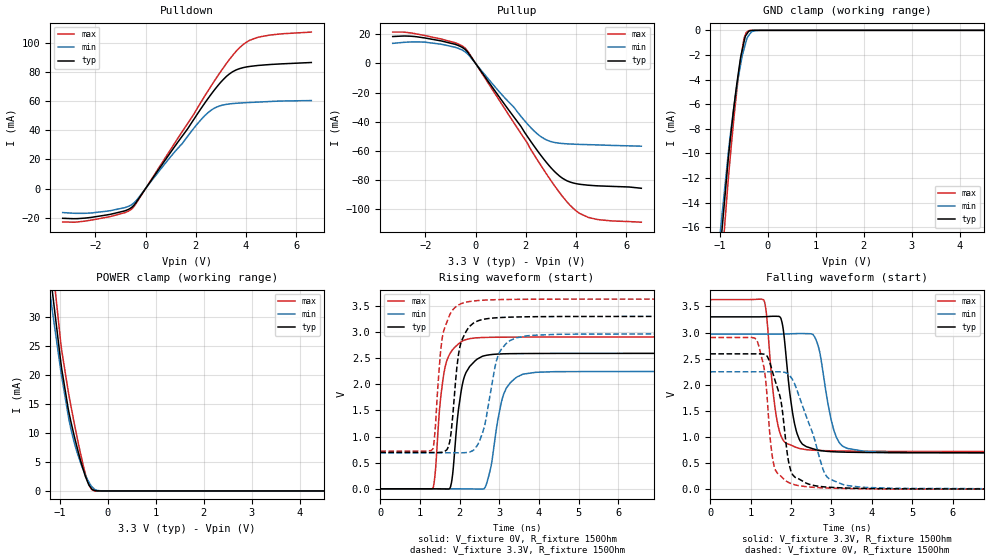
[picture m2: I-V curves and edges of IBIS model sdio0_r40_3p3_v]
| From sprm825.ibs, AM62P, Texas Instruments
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|   r40_3p3_v
[Model]   sdio0_r40_3p3_v
Model_type   I/O
Polarity   Non-Inverting
Enable   Active-High
Vinl = 0
Vinh = 0.8
Vmeas = 1.65
Vref = 3.3
Cref = 2pF
Rref = 100000
|   typ   min   max
C_comp   4.972pF   4.893pF   4.997pF
[Voltage Range]   3.3   2.97   3.63
[Temperature Range]   27   150   -40
[Pullup Reference]   3.3   2.97   3.63
[Pulldown Reference]   0   0   0
[Power Clamp Reference]   3.3   2.97   3.63
[GND Clamp Reference]   0   0   0
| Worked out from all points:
|   slope of the pulldown table from 0 to 0.495 V, typ, clamps not added: 40 ohm
|   slope of the pullup table from 0 to 0.495 V, typ, clamps not added: 40.9 ohm
|   GND clamp passes 1 mA (typ) near -0.50 V on its own axis
|   POWER clamp passes 1 mA (typ) near -0.39 V on its own axis
|   falling waveform, V_fixture 3.3V, R_fixture 150Ohm: 20-80 % time 250ps typ, 318ps min, 230ps max; typ from 3.3 V to 0.695 V
|   rising waveform, V_fixture 0V, R_fixture 150Ohm: 20-80 % time 239ps typ, 308ps min, 220ps max; typ from 0 V to 2.59 V
|   rising waveform, V_fixture 3.3V, R_fixture 150Ohm: 20-80 % time 225ps typ, 347ps min, 212ps max; typ from 0.695 V to 3.3 V
|   falling waveform, V_fixture 0V, R_fixture 150Ohm: 20-80 % time 333ps typ, 572ps min, 215ps max; typ from 2.59 V to 0 V
[Pulldown]
|   Voltage   I(typ)   I(min)   I(max)
-3.3V     -20.38mA   -16.44mA   -22.88mA
-2.706V   -20.6mA    -16.99mA   -22.89mA
-1.498V   -17.96mA   -15.4mA    -19.51mA
-825mV    -15.28mA   -13.07mA   -16.54mA
-537.9mV  -12.67mA   -10.87mA   -13.72mA
2.363V    58.69mA    50.02mA    63.57mA
2.779V    68.39mA    55.42mA    74.7mA
3.194V    76.41mA    57.61mA    85.09mA
3.452V    79.88mA    58.19mA    90.91mA
3.907V    82.92mA    58.75mA    98.97mA
4.481V    84.34mA    59.25mA    103.7mA
6.6V      86.36mA    60.28mA    107.2mA
[GND Clamp]
|   Voltage   I(typ)   I(min)   I(max)
-3.3V     -167.6mA   -127.2mA   -224.9mA
-1.013V   -18.75mA   -17.23mA   -21.53mA
-825mV    -10.45mA   -9.999mA   -12.11mA
-696.3mV  -5.878mA   -5.888mA   -6.705mA
-607.2mV  -3.274mA   -3.637mA   -3.484mA
-567.6mV  -2.2mA     -2.783mA   -2.434mA
-488.4mV  -789.6uA   -1.403mA   -561.5uA
-429mV    -244.2uA   -591.3uA   -118.2uA
-389.4mV  -55.96uA   -362.6uA   -19.71uA
-339.9mV  -12.99uA   -110.7uA   -2.821uA
-132mV    -51.25nA   -1.745uA   -80nA
6.6V      0A         0A         0A
[Pullup]
|   Voltage   I(typ)   I(min)   I(max)
-3.3V     18.39mA    13.72mA    21.44mA
-2.023V   17.42mA    14.55mA    19.09mA
-498.3mV  10.6mA     8.8mA      11.6mA
-270.6mV  6.667mA    5.678mA    7.277mA
2.402V    -58.33mA   -47.39mA   -64.49mA
2.798V    -67.3mA    -52.17mA   -75.04mA
3.194V    -74.84mA   -54.26mA   -84.94mA
3.472V    -78.72mA   -54.84mA   -91.28mA
3.887V    -81.85mA   -55.27mA   -99.21mA
4.155V    -82.75mA   -55.45mA   -102.8mA
4.788V    -83.74mA   -55.75mA   -106.6mA
6.6V      -85.46mA   -56.66mA   -108.7mA
[POWER Clamp]
|   Voltage   I(typ)   I(min)   I(max)
-3.3V     223mA      188.3mA    262.7mA
-1.201V   37.71mA    33.88mA    43.19mA
-1.191V   36.97mA    33.27mA    42.33mA
-1.152V   34.04mA    30.8mA     38.94mA
-983.4mV  22.42mA    20.88mA    25.69mA
-963.6mV  21.15mA    19.79mA    24.33mA
-805.2mV  13.3mA     12.07mA    16.24mA
-676.5mV  8.66mA     7.636mA    10.69mA
-488.4mV  3.032mA    3.154mA    3.565mA
-389.4mV  959.9uA    1.439mA    970.5uA
-290.4mV  115.1uA    394.2uA    56.37uA
6.6V      0A         0A         0A
[Ramp]
R_load = 150
|   typ   min   max
dV/dt_r   1.55495/2.38988e-10   1.3483/3.07596e-10   1.74325/2.20172e-10
dV/dt_f   1.5626/2.49912e-10   1.36811/3.16694e-10   1.74502/2.29481e-10
[Falling Waveform]
V_fixture = 3.3V
V_fixture_min = 2.97V
V_fixture_max = 3.63V
R_fixture = 150Ohm
C_fixture = 0F
|   Time   V(typ)   V(min)   V(max)
0s        3.3V       2.969V     3.63V
1.325ns   3.303V     2.97V      3.625V
1.675ns   3.31V      2.97V      1.228V
1.795ns   3.117V     2.971V     951mV
1.97ns    1.833V     2.975V     852.9mV
2.12ns    1.143V     2.979V     802.2mV
2.6ns     760.2mV    2.891V     744.2mV
3.055ns   716.1mV    1.139V     733.5mV
3.385ns   708.1mV    783.2mV    730.2mV
10ns      695.3mV    689.2mV    721.4mV
[Rising Waveform]
V_fixture = 0V
V_fixture_min = 0V
V_fixture_max = 0V
R_fixture = 150Ohm
C_fixture = 0F
|   Time   V(typ)   V(min)   V(max)
0s        312.6uV    651.3uV    206.8uV
1.325ns   271.9uV    472.7uV    9.314mV
1.63ns    -2.65mV    342.1uV    2.318V
1.795ns   124.6mV    381.9uV    2.633V
1.97ns    1.516V     258.5uV    2.772V
2.12ns    2.147V     -457.6uV   2.845V
2.645ns   2.55V      33.84mV    2.896V
3.105ns   2.582V     1.802V     2.901V
3.59ns    2.587V     2.192V     2.903V
10ns      2.592V     2.248V     2.906V
[Rising Waveform]
V_fixture = 3.3V
V_fixture_min = 2.97V
V_fixture_max = 3.63V
R_fixture = 150Ohm
C_fixture = 0F
|   Time   V(typ)   V(min)   V(max)
0s        695.3mV    689.2mV    721.4mV
1.32ns    695.3mV    689.1mV    756.6mV
1.575ns   702.1mV    689mV      2.945V
1.76ns    945.5mV    689mV      3.344V
1.93ns    2.325V     689mV      3.497V
2.045ns   2.82V      689.4mV    3.543V
2.485ns   3.219V     889.6mV    3.603V
2.975ns   3.274V     2.567V     3.619V
3.425ns   3.287V     2.887V     3.624V
10ns      3.3V       2.969V     3.63V
[Falling Waveform]
|Gnd
V_fixture = 0V
V_fixture_min = 0V
V_fixture_max = 0V
R_fixture = 150Ohm
C_fixture = 0F
|   Time   V(typ)   V(min)   V(max)
0s        2.592V     2.248V     2.906V
1.15ns    2.592V     2.248V     2.855V
1.35ns    2.58V      2.248V     2.228V
1.485ns   2.399V     2.248V     961.8mV
1.575ns   2.155V     2.248V     461.4mV
1.75ns    1.689V     2.247V     246.9mV
2.005ns   330.4mV    2.134V     105.5mV
2.83ns    43.67mV    308.5mV    23.86mV
3.28ns    24.19mV    90.69mV    13.79mV
10ns      313.4uV    651.4uV    206.8uV
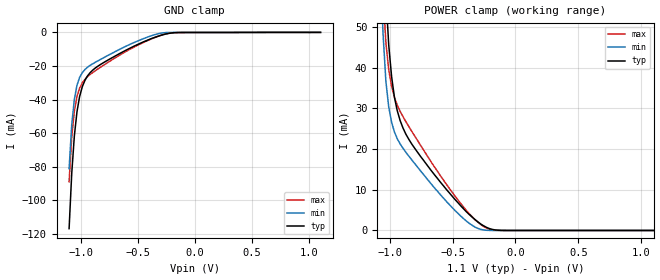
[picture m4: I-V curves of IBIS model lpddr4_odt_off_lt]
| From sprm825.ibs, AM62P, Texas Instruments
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|   Model lpddr4_odt_off_lt
[Model] lpddr4_odt_off_lt
Model_type Input
Polarity   Non-Inverting
Enable   Active-High
Vinl =  0.113V
Vinh =  0.253V
C_comp   2.918pF   2.672pF   2.927pF
[Model Spec]
Vinh   0.253V   0.247V   0.265V
Vinl   0.113V   0.107V   0.125V
[Temperature Range]   25.000   -40.000   -40.000
[Voltage Range]   1.100V   1.060V   1.170V
[C Comp Corner]
C_comp   2.927pF   2.672pF   2.918pF
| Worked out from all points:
|   GND clamp passes 1 mA (typ) near -0.26 V on its own axis
|   POWER clamp passes 1 mA (typ) near -0.24 V on its own axis
[GND_clamp]
|Voltage   I(typ)   I(min)   I(max)
-1.1V     -116.8mA   -81.16mA   -88.94mA
-1.077V   -83.94mA   -55mA      -62.39mA
-1.054V   -61.59mA   -39.8mA    -46.82mA
-1.031V   -47.19mA   -31.45mA   -38.12mA
-1.008V   -38.15mA   -26.79mA   -33.14mA
-985mV    -32.43mA   -23.99mA   -30.06mA
-962mV    -28.65mA   -22.13mA   -27.97mA
-917mV    -24.04mA   -19.67mA   -25.1mA
-871mV    -21.21mA   -17.8mA    -22.84mA
-481mV    -6.591mA   -4.569mA   -7.005mA
-229mV    -598.7uA   -44.99uA   -573.1uA
1.1V      0A         0A         0A
[POWER_clamp]
|Voltage   I(typ)   I(min)   I(max)
-1.1V     158.5mA    112mA      122.8mA
-1.054V   78.44mA    48.88mA    58.83mA
-1.031V   58.13mA    36.85mA    46.38mA
-1.008V   45.62mA    30.39mA    39.55mA
-985mV    37.81mA    26.62mA    35.43mA
-940mV    29.44mA    22.56mA    30.81mA
-894mV    25.17mA    20.21mA    27.98mA
-825mV    21.27mA    17.36mA    24.38mA
-367mV    3.909mA    1.752mA    4.095mA
-252mV    1.128mA    118.9uA    961uA
-160mV    128.1uA    2.966uA    54.3uA
1.1V      0A         0A         0A
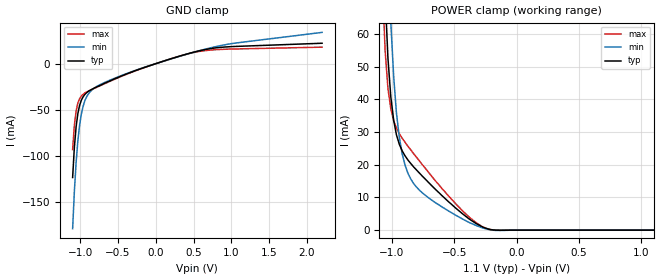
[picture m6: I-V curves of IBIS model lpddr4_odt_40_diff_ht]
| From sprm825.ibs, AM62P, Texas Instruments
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|   Model lpddr4_odt_40_diff_ht
[Model] lpddr4_odt_40_diff_ht
Model_type Input
Polarity   Non-Inverting
Enable   Active-High
Vinl =  0.113V
Vinh =  0.253V
C_comp   2.330pF   2.244pF   2.381pF
[Model Spec]
Vinh   0.253V   0.247V   0.265V
Vinl   0.113V   0.107V   0.125V
[Temperature Range]   25.000   0.125k   -40.000
[Voltage Range]   1.100V   1.060V   1.170V
[C Comp Corner]
C_comp   2.330pF   2.244pF   2.381pF
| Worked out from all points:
|   GND clamp passes 1 mA (typ) near -0.04 V on its own axis
|   POWER clamp passes 1 mA (typ) near -0.27 V on its own axis
[GND_clamp]
|Voltage   I(typ)   I(min)   I(max)
-1.1V     -123.6mA   -179.1mA   -93.24mA
-1.077V   -90.87mA   -138.8mA   -66.85mA
-1.054V   -68.63mA   -107.4mA   -51.44mA
-1.031V   -54.34mA   -83.93mA   -42.91mA
-1.008V   -45.42mA   -66.93mA   -38.11mA
-985mV    -39.79mA   -54.93mA   -35.23mA
-940mV    -33.58mA   -40.61mA   -31.98mA
-825mV    -27.02mA   -27.23mA   -27.3mA
-321mV    -9.177mA   -8.851mA   -9.456mA
550mV     13.39mA    13.42mA    12.85mA
940mV     18.16mA    20.83mA    15.65mA
2.2V      22.11mA    33.88mA    17.87mA
[POWER_clamp]
|Voltage   I(typ)   I(min)   I(max)
-1.1V     150.5mA    232.9mA    117.5mA
-1.077V   103.3mA    169.5mA    77.34mA
-1.054V   72.09mA    121.9mA    55.08mA
-1.031V   52.53mA    87.43mA    43.31mA
-1.008V   40.71mA    63.38mA    37.09mA
-963mV    29.15mA    35.85mA    31.21mA
-940mV    26.25mA    28.37mA    29.49mA
-871mV    21.44mA    17.41mA    25.65mA
-710mV    14.75mA    10.02mA    17.87mA
-390mV    3.719mA    2.548mA    4.353mA
-229mV    374uA      250uA      359.7uA
1.1V      0A         0A         0A
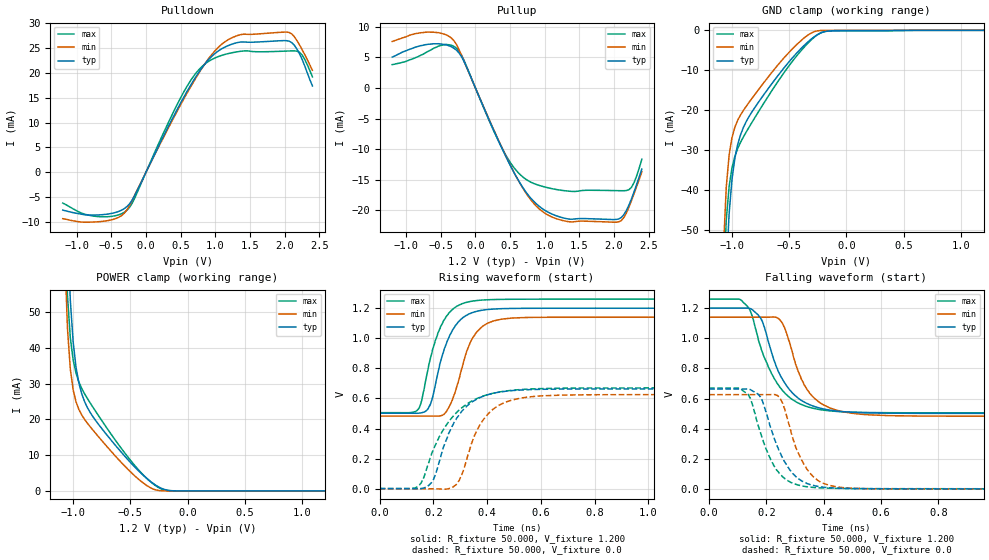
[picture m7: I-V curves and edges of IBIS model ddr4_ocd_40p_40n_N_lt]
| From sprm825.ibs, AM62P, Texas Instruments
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|   Model ddr4_ocd_40p_40n_N_lt
[Model] ddr4_ocd_40p_40n_N_lt
Model_type I/O
Polarity   Non-Inverting
Enable   Active-High
Vinl =  0.700V
Vinh =  0.900V
Vmeas =  0.600V
C_comp   2.139pF   2.037pF   2.245pF
[Model Spec]
Vinh   0.900V   0.820V   0.980V
Vinl   0.700V   0.620V   0.780V
Vmeas   0.600V   NA   NA
[Temperature Range]   25.000   -40.000   -40.000
[Voltage Range]   1.200V   1.140V   1.260V
[Pullup Reference]   1.200V   1.140V   1.260V
[Pulldown Reference]   0.0V   0.0V   0.0V
[C Comp Corner]
C_comp   2.139pF   2.037pF   2.245pF
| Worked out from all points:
|   slope of the pulldown table from 0 to 0.18 V, typ, clamps not added: 34.6 ohm
|   slope of the pullup table from 0 to 0.18 V, typ, clamps not added: 37.8 ohm
|   GND clamp passes 1 mA (typ) near -0.25 V on its own axis
|   POWER clamp passes 1 mA (typ) near -0.25 V on its own axis
|   rising waveform, R_fixture 50.000, V_fixture 1.200: 20-80 % time 72.1ps typ, 73.2ps min, 71ps max; typ from 0.502 V to 1.2 V
|   rising waveform, R_fixture 50.000, V_fixture 0.0: 20-80 % time 99.8ps typ, 93.5ps min, 129ps max; typ from 0.002 V to 0.664 V
|   falling waveform, R_fixture 50.000, V_fixture 1.200: 20-80 % time 93.8ps typ, 86.5ps min, 99.1ps max; typ from 1.2 V to 0.502 V
|   falling waveform, R_fixture 50.000, V_fixture 0.0: 20-80 % time 84.5ps typ, 76.2ps min, 78.6ps max; typ from 0.664 V to 0.002 V
[Pulldown]
|Voltage   I(typ)   I(min)   I(max)
-1.2V     -7.604mA   -9.324mA   -6.19mA
-718mV    -8.594mA   -9.972mA   -8.873mA
-421mV    -8.003mA   -9.223mA   -8.661mA
-272mV    -6.865mA   -7.502mA   -7.604mA
-161mV    -4.642mA   -4.549mA   -5.134mA
619mV     16.89mA    16.55mA    17.9mA
841mV     21.63mA    21.63mA    21.67mA
1.138V    25.17mA    26.22mA    23.69mA
1.398V    26.19mA    27.74mA    24.38mA
2.066V    26.34mA    28.1mA     24.39mA
2.252V    22.69mA    24.65mA    23.56mA
2.4V      17.35mA    20.51mA    19.18mA
[Pullup]
|Voltage   I(typ)   I(min)   I(max)
-1.2V     5.023mA    7.567mA    3.798mA
-606mV    7.199mA    9.095mA    6.434mA
-272mV    6.144mA    7.054mA    6.483mA
-161mV    4.243mA    4.267mA    4.42mA
247mV     -6.49mA    -6.402mA   -6.582mA
507mV     -12.75mA   -12.69mA   -12.24mA
804mV     -18.06mA   -18.33mA   -15.4mA
1.064V    -20.37mA   -20.85mA   -16.34mA
1.361V    -21.41mA   -21.85mA   -16.86mA
2.066V    -21.38mA   -21.86mA   -16.77mA
2.252V    -18.06mA   -18.36mA   -16.19mA
2.4V      -13.24mA   -13.7mA    -11.64mA
[GND_clamp]
|Voltage   I(typ)   I(min)   I(max)
-1.2V     -396.3mA   -359.8mA   -370.5mA
-1.075V   -83.02mA   -54.49mA   -63.08mA
-1.05V    -59.94mA   -39.12mA   -47.32mA
-1.025V   -45.76mA   -31.12mA   -38.96mA
-1V       -37.22mA   -26.8mA    -34.32mA
-950mV    -28.5mA    -22.45mA   -29.5mA
-900mV    -24.23mA   -19.99mA   -26.62mA
-800mV    -19.26mA   -16.03mA   -21.8mA
-550mV    -9.545mA   -7.027mA   -10.77mA
-350mV    -3.249mA   -1.463mA   -3.61mA
-150mV    -148.5uA   -4.426uA   -178.6uA
1.2V      0A         0A         0A
[POWER_clamp]
|Voltage   I(typ)   I(min)   I(max)
-1.2V     594.8mA    611.1mA    623.3mA
-1.075V   106.2mA    68.15mA    77.8mA
-1.05V    73.23mA    45.49mA    54.67mA
-1.025V   53.34mA    34.11mA    42.85mA
-1V       41.61mA    28.23mA    36.57mA
-975mV    34.56mA    24.88mA    32.87mA
-950mV    30.12mA    22.73mA    30.42mA
-900mV    24.94mA    19.97mA    27.12mA
-825mV    20.64mA    16.92mA    23.28mA
-375mV    4.008mA    1.916mA    4.058mA
-175mV    200.6uA    5.445uA    99.21uA
1.2V      0A         0A         0A
[Ramp]
| variable   typ   min   max
dV/dt_r   0.397/99.237p   0.376/93.412p   0.400/0.130n
dV/dt_f   0.419/93.068p   0.394/85.537p   0.452/99.140p
R_load = 60.000
[Rising Waveform]
R_fixture= 50.000
V_fixture= 1.200
V_fixture_min= 1.140
V_fixture_max= 1.260
|time   V(typ)   V(min)   V(max)
0s        502.1mV    483mV      505.9mV
145ps     502.5mV    483mV      532.4mV
187ps     553.2mV    483mV      853.3mV
238ps     912.8mV    492.9mV    1.117V
280ps     1.08V      637.4mV    1.204V
323ps     1.152V     909.8mV    1.238V
347ps     1.171V     1.005V     1.247V
424ps     1.194V     1.115V     1.257V
544ps     1.199V     1.138V     1.259V
3ns       1.2V       1.14V      1.26V
[Rising Waveform]
R_fixture= 50.000
V_fixture= 0.0
V_fixture_min= 0.0
V_fixture_max= 0.0
|time   V(typ)   V(min)   V(max)
0s        1.58mV     142.5uV    2.722mV
136ps     1.49mV     136.7uV    9.821mV
161ps     4.365mV    137.8uV    60.31mV
185ps     27.05mV    133uV      187.8mV
274ps     429.4mV    13.83mV    483.7mV
304ps     510.5mV    84.76mV    535.9mV
381ps     611.7mV    448mV      613.6mV
471ps     648.5mV    577.3mV    650mV
791ps     663.3mV    624.8mV    669.7mV
3ns       663.6mV    626.6mV    670.2mV
[Falling Waveform]
R_fixture= 50.000
V_fixture= 1.200
V_fixture_min= 1.140
V_fixture_max= 1.260
|time   V(typ)   V(min)   V(max)
0s        1.2V       1.14V      1.26V
106ps     1.2V       1.14V      1.259V
139ps     1.199V     1.14V      1.199V
184ps     1.12V      1.14V      916.6mV
245ps     767.3mV    1.126V     681.9mV
263ps     706.6mV    1.071V     639.9mV
330ps     578.9mV    697.1mV    555.1mV
399ps     531.6mV    558.6mV    523.8mV
629ps     503.6mV    487.3mV    506.8mV
3ns       502.1mV    483mV      505.9mV
[Falling Waveform]
R_fixture= 50.000
V_fixture= 0.0
V_fixture_min= 0.0
V_fixture_max= 0.0
|time   V(typ)   V(min)   V(max)
0s        663.6mV    626.5mV    670.2mV
136ps     663.4mV    626.5mV    628.5mV
184ps     594mV      626.5mV    346.6mV
241ps     270.2mV    616.1mV    115.3mV
263ps     182.7mV    535mV      72.65mV
291ps     105.1mV    345.1mV    40.51mV
349ps     33.08mV    113.9mV    14.25mV
421ps     9.467mV    24.6mV     6.341mV
559ps     3.116mV    2.909mV    3.715mV
3ns       1.579mV    143.3uV    2.722mV
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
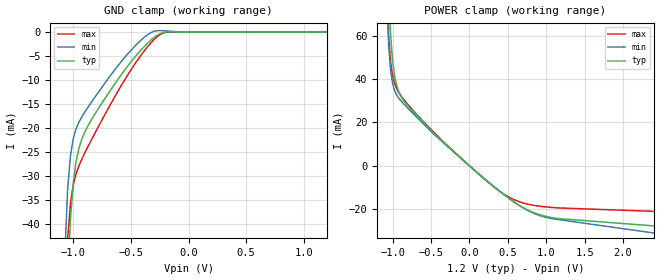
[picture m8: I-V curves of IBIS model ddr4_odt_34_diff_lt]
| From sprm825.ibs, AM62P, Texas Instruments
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|   Model ddr4_odt_34_diff_lt
[Model] ddr4_odt_34_diff_lt
Model_type Input
Polarity   Non-Inverting
Enable   Active-High
Vinl =  0.700V
Vinh =  0.900V
C_comp   2.071pF   1.855pF   2.274pF
[Model Spec]
Vinh   0.900V   0.820V   0.980V
Vinl   0.700V   0.620V   0.780V
[Temperature Range]   25.000   -40.000   -40.000
[Voltage Range]   1.200V   1.140V   1.260V
[C Comp Corner]
C_comp   2.071pF   1.855pF   2.274pF
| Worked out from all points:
|   GND clamp passes 1 mA (typ) near -0.29 V on its own axis
|   POWER clamp passes 1 mA (typ) near -0.03 V on its own axis
[GND_clamp]
|Voltage   I(typ)   I(min)   I(max)
-1.2V     -382.1mA   -347.3mA   -359.6mA
-1.075V   -74.28mA   -47.38mA   -57.99mA
-1.05V    -52.21mA   -32.92mA   -43.22mA
-1.025V   -38.97mA   -25.72mA   -35.73mA
-1V       -31.31mA   -22.09mA   -31.79mA
-975mV    -26.84mA   -20.05mA   -29.44mA
-950mV    -24.08mA   -18.69mA   -27.78mA
-875mV    -19.62mA   -15.74mA   -23.95mA
-725mV    -13.82mA   -10.61mA   -17.14mA
-350mV    -2.185mA   -466.7uA   -2.909mA
-175mV    46.93uA    189.5uA    -1.97uA
1.2V      0A         0A         0A
[POWER_clamp]
|Voltage   I(typ)   I(min)   I(max)
-1.2V     600.8mA    620.1mA    627.8mA
-1.075V   112.9mA    77.68mA    82.65mA
-1.05V    80.14mA    55.13mA    59.6mA
-1.025V   60.4mA     43.86mA    47.88mA
-1V       48.79mA    38.09mA    41.69mA
-975mV    41.87mA    34.87mA    38.11mA
-925mV    34.67mA    31.41mA    34.11mA
-825mV    28.64mA    27.43mA    29.31mA
-450mV    14.65mA    14.15mA    14.96mA
425mV     -12.7mA    -12.6mA    -12.51mA
1.025V    -23.58mA   -24.06mA   -19.1mA
2.4V      -27.74mA   -31.01mA   -21.04mA
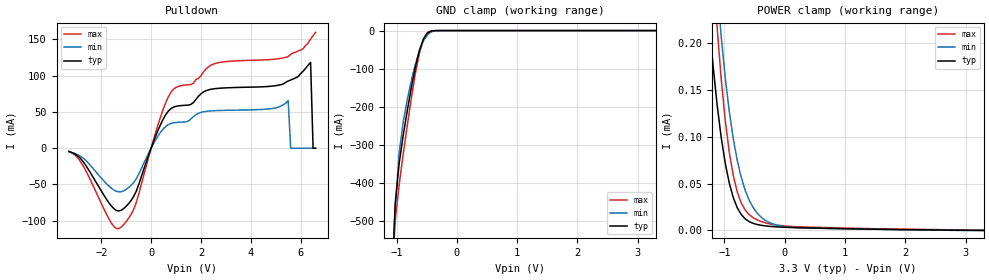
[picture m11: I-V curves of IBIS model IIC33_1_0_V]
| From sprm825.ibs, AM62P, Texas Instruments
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|2EMMC ********************** End EMMC **********************************
|1I2C ***********************Start I2C 1.8V **********************************
|   Model IIC33_1_0_V
[Model]  IIC33_1_0_V
Model_type I/O_open_drain
Polarity   Non-Inverting
Enable   Active-High
Vinl =  0.990V
Vinh =  2.310V
Vmeas =  1.650V
Cref =  50.000pF
Rref =  1.000M
Vref =  0.0V
C_comp   6.002pF   5.980pF   6.005pF
[Model Spec]
Vinh   2.310V   2.079V   2.541V
Vinl   0.990V   0.891V   1.089V
Vmeas   1.650V   NA   NA
Vref   0.0V   NA   NA
Cref   50.000pF   NA   NA
Rref   1.000M   NA   NA
[Temperature Range]   25.000   0.125k   -40.000
[Voltage Range]   3.300V   2.970V   3.630V
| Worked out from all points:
|   slope of the pulldown table from 0 to 0.495 V, typ, clamps not added: 12.2 ohm
|   GND clamp passes 1 mA (typ) near -0.42 V on its own axis
|   POWER clamp passes 1 mA (typ) near -1.87 V on its own axis
[Pulldown]
|Voltage   I(typ)   I(min)   I(max)
-3.3V     -4.534mA   -4.863mA   -4.201mA
-2.8V     -15.43mA   -11.77mA   -20.27mA
-1.7V     -74.97mA   -51.98mA   -96.98mA
-1.3V     -86.65mA   -60.26mA   -111mA
-600mV    -59.58mA   -42.4mA    -75.45mA
700mV     51.54mA    32.76mA    71.48mA
2.3V      80.48mA    51.2mA     112.2mA
5.5V      92.79mA    65.93mA    126.6mA
5.6V      94.04mA    -11.4nA    129.2mA
6.4V      118.4mA    -2.9uA     150.4mA
6.5V      -600nA     -3.9uA     155.5mA
6.6V      -700nA     -18.4uA    159.8mA
[GND_clamp]
|Voltage   I(typ)   I(min)   I(max)
-3.3V     -44.71A    -41.78A    -47.63A
-1.089V   -701.8mA   -759mA     -699.7mA
-1.022V   -456.1mA   -464.3mA   -499.5mA
-955mV    -347.7mA   -319.9mA   -403.8mA
-888mV    -274.3mA   -239.2mA   -324mA
-821mV    -209.8mA   -180.9mA   -248.7mA
-687mV    -96.09mA   -88.17mA   -112.2mA
-620mV    -52.41mA   -52.78mA   -58.95mA
-553mV    -22.16mA   -26.73mA   -22.67mA
-486mV    -6.181mA   -10.55mA   -4.967mA
-285mV    -10.13uA   -113uA     -1.594uA
3.3V      0A         0A         0A
[POWER_clamp]
|Voltage   I(typ)   I(min)   I(max)
-3.266V   6.374A     1.828A     18.02A
-1.256V   225.2uA    392.2uA    358.5uA
-1.122V   134.5uA    260.2uA    217.3uA
-1.055V   99.94uA    207.9uA    162.7uA
-988mV    72.22uA    163.9uA    118.5uA
-921mV    50.87uA    127.6uA    84.13uA
-854mV    35.18uA    98.07uA    58.72uA
-720mV    16.94uA    56.36uA    29.14uA
-586mV    9.315uA    31.79uA    16.69uA
-318mV    4.878uA    10.61uA    8.054uA
17mV      3.368uA    4.051uA    4.707uA
3.3V      0A         0A         270nA
[Ramp]
| variable   typ   min   max
dV/dt_r   1.555/0.132n   1.078/0.222n   1.837/0.142n
dV/dt_f   0.277/17.228n   0.127/16.535n   0.545/17.144n
R_load = 50.000
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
